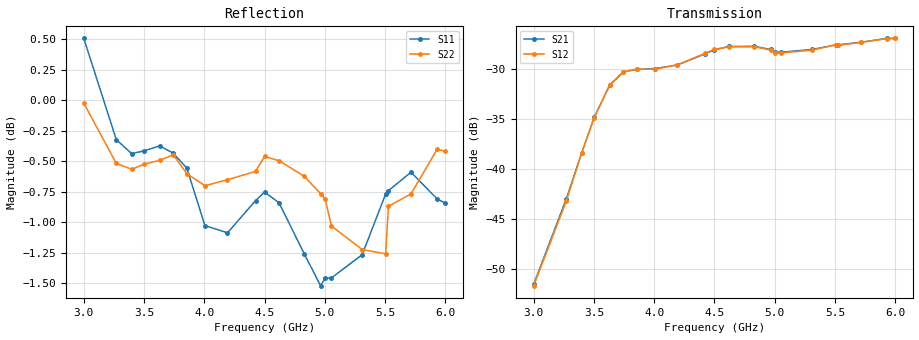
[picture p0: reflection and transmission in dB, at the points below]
!  26/11/2025  16:47:16
! Ref Plane: 0.000 mm
# MHZ S MA R  50
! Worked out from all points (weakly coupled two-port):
!   401 points, 3 GHz to 6 GHz, reference 50 ohm
!   highest |S21| = -26.96 dB at 5.933 GHz (marker M1); lowest = -51.5 dB at 3 GHz (marker M2)
!   lowest |S11| = -1.5 dB at 4.965 GHz (marker M3), VSWR 11.46, Z = 9.74 - j55 ohm
!   |S11| at or under -10 dB: nowhere
!   |S22| runs from -1.3 to 0.1 dB; largest |S21 - S12| = 0.0018
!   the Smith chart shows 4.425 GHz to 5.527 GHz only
!   S11 on the Smith chart (normalised r, x): 4.425 GHz: 0.09, +1.00; 4.62 GHz: 0.94, +4.20; 4.83 GHz: 0.56, -2.54; 5.055 GHz: 0.12, -0.70; 5.31 GHz: 0.07, -0.01; 5.527 GHz: 0.06, +0.59
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3000  1.06 -136.8  0.002666 50.2  0.002625 53.1  0.9972 -105.8
3270  0.9635 152.8  0.007098 -16.6  0.006924 -12.9  0.9421 -170.7
3397.5  0.9508 109.4  0.01201 -55.9  0.01203 -55.0  0.9369 150.5
3502.5  0.9534 66.7  0.01813 -96.1  0.01805 -95.0  0.9415 112.5
3630  0.9578 11.9  0.0262 -152.1  0.0263 -150.8  0.9448 57.3
3742.5  0.9512 -37.4  0.0305 158.2  0.03052 159.7  0.9498 9.0
3855  0.9379 -82.7  0.03149 112.1  0.03153 113.5  0.933 -37.2
4005  0.8885 -136.3  0.03172 59.1  0.0315 60.2  0.9225 -89.4
4192.5  0.8824 164.1  0.03306 0.7  0.03311 2.8  0.9277 -148.2
4425  0.9096 89.8  0.03765 -71.1  0.03782 -69.5  0.935 140.3
4500  0.9169 65.4  0.03937 -95.6  0.03952 -94.2  0.9483 117.3
4620  0.9078 25.6  0.04091 -134.7  0.0407 -133.6  0.9445 79.5
4830  0.865 -41.4  0.04094 158.3  0.04081 159.9  0.9307 16.5
4965  0.8395 -83.5  0.03951 118.3  0.03923 119.7  0.9155 -22.3
5002.5  0.8455 -94.9  0.03825 107.9  0.03785 109.1  0.9111 -34.1
5055  0.8457 -109.5  0.03828 93.1  0.03797 94.0  0.8881 -50.0
5310  0.8644 -179.1  0.0395 24.1  0.03919 25.5  0.8686 -123.9
5505  0.9154 123.0  0.04159 -30.3  0.04173 -28.4  0.8651 -176.2
5527.5  0.9182 118.7  0.04169 -35.6  0.04141 -33.6  0.9047 178.2
5715  0.9343 63.9  0.0429 -90.3  0.04283 -88.0  0.9154 124.1
5932.5  0.911 1.4  0.04487 -152.4  0.04476 -150.7  0.9548 67.4
6000  0.9075 -18.4  0.04485 -171.7  0.04481 -170.2  0.9529 50.2
